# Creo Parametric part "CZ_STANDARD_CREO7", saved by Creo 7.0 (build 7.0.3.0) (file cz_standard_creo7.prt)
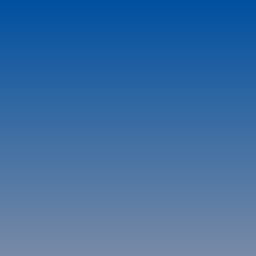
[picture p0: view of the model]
Units: Custom; MM, KILOGRAM, SECS

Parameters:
  BEARBEITER = "."
  ERSTELLUNGSDATUM = "."
  KONSTRUKTIONSGRUPPE = "."
  ZEICHNUNGSNUMMER = "000000-0000-000/01"
  TEILDOKUMENT = "001"
  VERSION = "01"
  MATERIALNUMMER = "000000-0000-000"
  KOMP_STUFE = "T"
  KOMP_CHAR = "M"
  BENENNUNG = "XXXXX"

Other parameters: PREIS

Created from: CZ_STANDARD_CREO4.PRT

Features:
  1. datum plane "Y-Z"
  2. datum plane "X-Z"
  3. datum plane "X-Y"
  4. coordinate system
  5. datum axis
  6. datum axis
  7. datum axis

Other named items: X0Y0Z0, X-ACHSE, Y-ACHSE, Z-ACHSE

Layers: ACHSEN, BOHRUNGSNOTIZEN, EBENEN, FLAECHEN, GEWINDE, KOORDSYS, KURVEN, PUNKTE, RUNDUNGEN, S_ACHSEN, S_EBENEN, S_KOORDSYS, VERBFLAECHE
